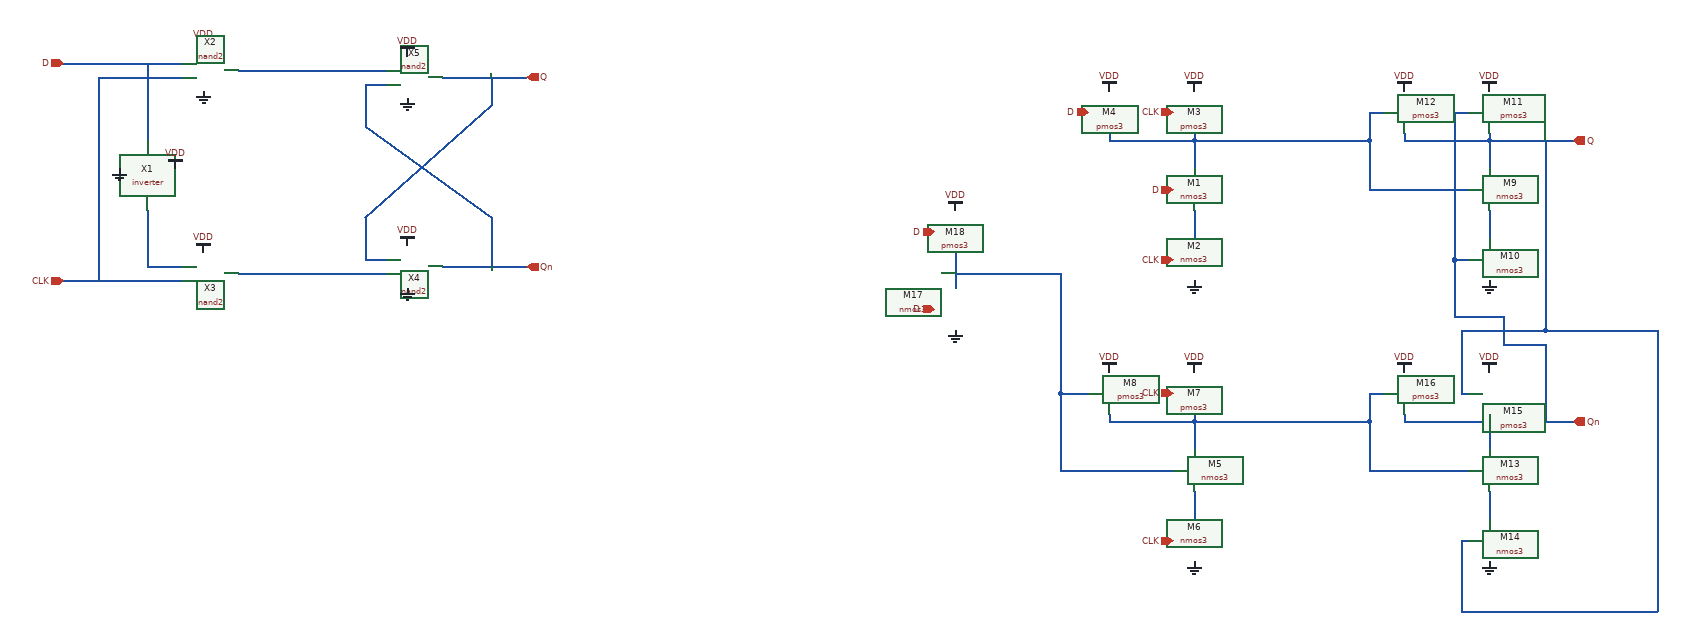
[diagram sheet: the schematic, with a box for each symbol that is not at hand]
v {xschem version=2.9.9 file_version=1.2 }
G {}
K {}
V {}
S {}
E {}
N 240 -670 410 -670 { lab=CLK}
N 240 -980 410 -980 { lab=D}
N 780 -960 900 -960 { lab=Q}
N 780 -690 900 -690 { lab=Qn}
N 490 -970 700 -970 { lab=#net1}
N 490 -680 700 -680 { lab=#net2}
N 670 -700 700 -700 { lab=Q}
N 670 -760 670 -700 { lab=Q}
N 670 -760 850 -920 { lab=Q}
N 850 -960 850 -920 { lab=Q}
N 670 -950 700 -950 { lab=Qn}
N 670 -950 670 -890 { lab=Qn}
N 670 -890 850 -760 { lab=Qn}
N 850 -760 850 -690 { lab=Qn}
N 290 -960 410 -960 { lab=CLK}
N 290 -960 290 -670 { lab=CLK}
N 360 -980 360 -870 { lab=D}
N 360 -770 360 -690 { lab=#net3}
N 360 -690 410 -690 { lab=#net3}
N 1730 -880 1730 -870 { lab=#net4}
N 1730 -870 1850 -870 { lab=#net4}
N 1850 -880 1850 -870 { lab=#net4}
N 1850 -870 1850 -830 { lab=#net4}
N 1850 -770 1850 -730 { lab=#net5}
N 1730 -480 1730 -470 { lab=#net6}
N 1730 -470 1850 -470 { lab=#net6}
N 1850 -480 1850 -470 { lab=#net6}
N 1850 -470 1850 -430 { lab=#net6}
N 1850 -370 1850 -330 { lab=#net7}
N 2150 -880 2150 -870 { lab=Q}
N 2150 -870 2270 -870 { lab=Q}
N 2270 -880 2270 -870 { lab=Q}
N 2270 -870 2270 -830 { lab=Q}
N 2270 -770 2270 -730 { lab=#net8}
N 2150 -480 2150 -470 { lab=#net9}
N 2150 -470 2270 -470 { lab=#net9}
N 2270 -480 2270 -470 { lab=#net9}
N 2270 -470 2270 -430 { lab=#net9}
N 2270 -370 2270 -330 { lab=#net10}
N 1510 -710 1510 -700 { lab=#net11}
N 1510 -700 1510 -660 { lab=#net11}
N 1510 -680 1660 -680 { lab=#net11}
N 1660 -680 1660 -510 { lab=#net11}
N 1660 -510 1700 -510 { lab=#net11}
N 1660 -510 1660 -400 { lab=#net11}
N 1660 -400 1820 -400 { lab=#net11}
N 2270 -870 2390 -870 { lab=Q}
N 2270 -470 2390 -470 { lab=Qn}
N 1850 -870 2100 -870 {}
N 2100 -910 2100 -870 {}
N 2100 -910 2120 -910 {}
N 2100 -870 2100 -800 {}
N 2100 -800 2240 -800 {}
N 1850 -470 2100 -470 {}
N 2100 -510 2100 -470 {}
N 2100 -510 2120 -510 {}
N 2100 -470 2100 -400 {}
N 2100 -400 2240 -400 {}
N 2350 -870 2350 -600 {}
N 2230 -600 2350 -600 {}
N 2230 -600 2230 -510 {}
N 2230 -510 2240 -510 {}
N 2350 -600 2510 -600 {}
N 2510 -600 2510 -200 {}
N 2230 -200 2510 -200 {}
N 2230 -300 2230 -200 {}
N 2230 -300 2240 -300 {}
N 2350 -580 2350 -470 {}
N 2290 -580 2350 -580 {}
N 2290 -620 2290 -580 {}
N 2220 -620 2290 -620 {}
N 2220 -700 2220 -620 {}
N 2220 -700 2240 -700 {}
N 2220 -910 2220 -700 {}
N 2220 -910 2240 -910 {}
C {devices/ipin.sym} 240 -980 0 0 {name=p3 lab=D}
C {devices/iopin.sym} 240 -670 2 0 {name=p7 lab=CLK}
C {devices/opin.sym} 900 -690 0 0 {name=p6 lab=Qn}
C {devices/opin.sym} 900 -960 0 0 {name=p8 lab=Q}
C {madvlsi/vdd.sym} 440 -1000 0 0 {name=l3 lab=VDD}
C {madvlsi/vdd.sym} 440 -710 0 0 {name=l4 lab=VDD}
C {madvlsi/gnd.sym} 440 -940 0 0 {name=l5 lab=GND}
C {madvlsi/gnd.sym} 440 -650 0 0 {name=l6 lab=GND}
C {/home/madvlsi/Documents/MADVLSI-Final_Project/schematic/nand2.sym} 370 -970 0 0 {name=X2}
C {/home/madvlsi/Documents/MADVLSI-Final_Project/schematic/nand2.sym} 370 -680 0 0 {name=X3}
C {/home/madvlsi/Documents/MADVLSI-Final_Project/schematic/nand2.sym} 660 -690 0 0 {name=X4}
C {/home/madvlsi/Documents/MADVLSI-Final_Project/schematic/nand2.sym} 660 -960 0 0 {name=X5}
C {madvlsi/vdd.sym} 730 -990 0 0 {name=l7 lab=VDD}
C {madvlsi/gnd.sym} 730 -930 0 0 {name=l8 lab=GND}
C {madvlsi/vdd.sym} 730 -720 0 0 {name=l9 lab=VDD}
C {madvlsi/gnd.sym} 730 -660 0 0 {name=l10 lab=GND}
C {/home/madvlsi/Documents/MADVLSI-Final_Project/schematic/inverter.sym} 360 -830 1 0 {name=X1 Wp=1 Lp=0.15 WW=1 LL=0.15}
C {madvlsi/vdd.sym} 400 -830 1 0 {name=l1 lab=VDD}
C {madvlsi/gnd.sym} 320 -830 1 0 {name=l2 lab=GND}
C {madvlsi/nmos3.sym} 1850 -800 0 0 {name=M1
L=0.15
W=1
body=GND
nf=1
mult=1
ad="'int((nf+1)/2) * W/nf * 0.29'" 
pd="'2*int((nf+1)/2) * (W/nf + 0.29)'"
as="'int((nf+2)/2) * W/nf * 0.29'" 
ps="'2*int((nf+2)/2) * (W/nf + 0.29)'"
nrd="'0.29 / W'" nrs="'0.29 / W'"
sa=0 sb=0 sd=0
model=nfet_01v8
spiceprefix=X
}
C {madvlsi/nmos3.sym} 1850 -700 0 0 {name=M2
L=0.15
W=1
body=GND
nf=1
mult=1
ad="'int((nf+1)/2) * W/nf * 0.29'" 
pd="'2*int((nf+1)/2) * (W/nf + 0.29)'"
as="'int((nf+2)/2) * W/nf * 0.29'" 
ps="'2*int((nf+2)/2) * (W/nf + 0.29)'"
nrd="'0.29 / W'" nrs="'0.29 / W'"
sa=0 sb=0 sd=0
model=nfet_01v8
spiceprefix=X
}
C {madvlsi/pmos3.sym} 1850 -910 0 0 {name=M3
L=0.15
W=1
body=VDD
nf=1
mult=1
ad="'int((nf+1)/2) * W/nf * 0.29'" 
pd="'2*int((nf+1)/2) * (W/nf + 0.29)'"
as="'int((nf+2)/2) * W/nf * 0.29'" 
ps="'2*int((nf+2)/2) * (W/nf + 0.29)'"
nrd="'0.29 / W'" nrs="'0.29 / W'"
sa=0 sb=0 sd=0
model=pfet_01v8
spiceprefix=X
}
C {madvlsi/pmos3.sym} 1730 -910 0 0 {name=M4
L=0.15
W=1
body=VDD
nf=1
mult=1
ad="'int((nf+1)/2) * W/nf * 0.29'" 
pd="'2*int((nf+1)/2) * (W/nf + 0.29)'"
as="'int((nf+2)/2) * W/nf * 0.29'" 
ps="'2*int((nf+2)/2) * (W/nf + 0.29)'"
nrd="'0.29 / W'" nrs="'0.29 / W'"
sa=0 sb=0 sd=0
model=pfet_01v8
spiceprefix=X
}
C {madvlsi/vdd.sym} 1730 -940 0 0 {name=l11 lab=VDD}
C {madvlsi/vdd.sym} 1850 -940 0 0 {name=l12 lab=VDD}
C {madvlsi/gnd.sym} 1850 -670 0 0 {name=l13 lab=GND}
C {madvlsi/nmos3.sym} 1850 -400 0 0 {name=M5
L=0.15
W=1
body=GND
nf=1
mult=1
ad="'int((nf+1)/2) * W/nf * 0.29'" 
pd="'2*int((nf+1)/2) * (W/nf + 0.29)'"
as="'int((nf+2)/2) * W/nf * 0.29'" 
ps="'2*int((nf+2)/2) * (W/nf + 0.29)'"
nrd="'0.29 / W'" nrs="'0.29 / W'"
sa=0 sb=0 sd=0
model=nfet_01v8
spiceprefix=X
}
C {madvlsi/nmos3.sym} 1850 -300 0 0 {name=M6
L=0.15
W=1
body=GND
nf=1
mult=1
ad="'int((nf+1)/2) * W/nf * 0.29'" 
pd="'2*int((nf+1)/2) * (W/nf + 0.29)'"
as="'int((nf+2)/2) * W/nf * 0.29'" 
ps="'2*int((nf+2)/2) * (W/nf + 0.29)'"
nrd="'0.29 / W'" nrs="'0.29 / W'"
sa=0 sb=0 sd=0
model=nfet_01v8
spiceprefix=X
}
C {madvlsi/pmos3.sym} 1850 -510 0 0 {name=M7
L=0.15
W=1
body=VDD
nf=1
mult=1
ad="'int((nf+1)/2) * W/nf * 0.29'" 
pd="'2*int((nf+1)/2) * (W/nf + 0.29)'"
as="'int((nf+2)/2) * W/nf * 0.29'" 
ps="'2*int((nf+2)/2) * (W/nf + 0.29)'"
nrd="'0.29 / W'" nrs="'0.29 / W'"
sa=0 sb=0 sd=0
model=pfet_01v8
spiceprefix=X
}
C {madvlsi/pmos3.sym} 1730 -510 0 0 {name=M8
L=0.15
W=1
body=VDD
nf=1
mult=1
ad="'int((nf+1)/2) * W/nf * 0.29'" 
pd="'2*int((nf+1)/2) * (W/nf + 0.29)'"
as="'int((nf+2)/2) * W/nf * 0.29'" 
ps="'2*int((nf+2)/2) * (W/nf + 0.29)'"
nrd="'0.29 / W'" nrs="'0.29 / W'"
sa=0 sb=0 sd=0
model=pfet_01v8
spiceprefix=X
}
C {madvlsi/vdd.sym} 1730 -540 0 0 {name=l14 lab=VDD}
C {madvlsi/vdd.sym} 1850 -540 0 0 {name=l15 lab=VDD}
C {madvlsi/gnd.sym} 1850 -270 0 0 {name=l16 lab=GND}
C {madvlsi/nmos3.sym} 2270 -800 0 0 {name=M9
L=0.15
W=1
body=GND
nf=1
mult=1
ad="'int((nf+1)/2) * W/nf * 0.29'" 
pd="'2*int((nf+1)/2) * (W/nf + 0.29)'"
as="'int((nf+2)/2) * W/nf * 0.29'" 
ps="'2*int((nf+2)/2) * (W/nf + 0.29)'"
nrd="'0.29 / W'" nrs="'0.29 / W'"
sa=0 sb=0 sd=0
model=nfet_01v8
spiceprefix=X
}
C {madvlsi/nmos3.sym} 2270 -700 0 0 {name=M10
L=0.15
W=1
body=GND
nf=1
mult=1
ad="'int((nf+1)/2) * W/nf * 0.29'" 
pd="'2*int((nf+1)/2) * (W/nf + 0.29)'"
as="'int((nf+2)/2) * W/nf * 0.29'" 
ps="'2*int((nf+2)/2) * (W/nf + 0.29)'"
nrd="'0.29 / W'" nrs="'0.29 / W'"
sa=0 sb=0 sd=0
model=nfet_01v8
spiceprefix=X
}
C {madvlsi/pmos3.sym} 2270 -910 0 0 {name=M11
L=0.15
W=1
body=VDD
nf=1
mult=1
ad="'int((nf+1)/2) * W/nf * 0.29'" 
pd="'2*int((nf+1)/2) * (W/nf + 0.29)'"
as="'int((nf+2)/2) * W/nf * 0.29'" 
ps="'2*int((nf+2)/2) * (W/nf + 0.29)'"
nrd="'0.29 / W'" nrs="'0.29 / W'"
sa=0 sb=0 sd=0
model=pfet_01v8
spiceprefix=X
}
C {madvlsi/pmos3.sym} 2150 -910 0 0 {name=M12
L=0.15
W=1
body=VDD
nf=1
mult=1
ad="'int((nf+1)/2) * W/nf * 0.29'" 
pd="'2*int((nf+1)/2) * (W/nf + 0.29)'"
as="'int((nf+2)/2) * W/nf * 0.29'" 
ps="'2*int((nf+2)/2) * (W/nf + 0.29)'"
nrd="'0.29 / W'" nrs="'0.29 / W'"
sa=0 sb=0 sd=0
model=pfet_01v8
spiceprefix=X
}
C {madvlsi/vdd.sym} 2150 -940 0 0 {name=l17 lab=VDD}
C {madvlsi/vdd.sym} 2270 -940 0 0 {name=l18 lab=VDD}
C {madvlsi/gnd.sym} 2270 -670 0 0 {name=l19 lab=GND}
C {madvlsi/nmos3.sym} 2270 -400 0 0 {name=M13
L=0.15
W=1
body=GND
nf=1
mult=1
ad="'int((nf+1)/2) * W/nf * 0.29'" 
pd="'2*int((nf+1)/2) * (W/nf + 0.29)'"
as="'int((nf+2)/2) * W/nf * 0.29'" 
ps="'2*int((nf+2)/2) * (W/nf + 0.29)'"
nrd="'0.29 / W'" nrs="'0.29 / W'"
sa=0 sb=0 sd=0
model=nfet_01v8
spiceprefix=X
}
C {madvlsi/nmos3.sym} 2270 -300 0 0 {name=M14
L=0.15
W=1
body=GND
nf=1
mult=1
ad="'int((nf+1)/2) * W/nf * 0.29'" 
pd="'2*int((nf+1)/2) * (W/nf + 0.29)'"
as="'int((nf+2)/2) * W/nf * 0.29'" 
ps="'2*int((nf+2)/2) * (W/nf + 0.29)'"
nrd="'0.29 / W'" nrs="'0.29 / W'"
sa=0 sb=0 sd=0
model=nfet_01v8
spiceprefix=X
}
C {madvlsi/pmos3.sym} 2270 -510 0 0 {name=M15
L=0.15
W=1
body=VDD
nf=1
mult=1
ad="'int((nf+1)/2) * W/nf * 0.29'" 
pd="'2*int((nf+1)/2) * (W/nf + 0.29)'"
as="'int((nf+2)/2) * W/nf * 0.29'" 
ps="'2*int((nf+2)/2) * (W/nf + 0.29)'"
nrd="'0.29 / W'" nrs="'0.29 / W'"
sa=0 sb=0 sd=0
model=pfet_01v8
spiceprefix=X
}
C {madvlsi/pmos3.sym} 2150 -510 0 0 {name=M16
L=0.15
W=1
body=VDD
nf=1
mult=1
ad="'int((nf+1)/2) * W/nf * 0.29'" 
pd="'2*int((nf+1)/2) * (W/nf + 0.29)'"
as="'int((nf+2)/2) * W/nf * 0.29'" 
ps="'2*int((nf+2)/2) * (W/nf + 0.29)'"
nrd="'0.29 / W'" nrs="'0.29 / W'"
sa=0 sb=0 sd=0
model=pfet_01v8
spiceprefix=X
}
C {madvlsi/vdd.sym} 2150 -540 0 0 {name=l20 lab=VDD}
C {madvlsi/vdd.sym} 2270 -540 0 0 {name=l21 lab=VDD}
C {madvlsi/gnd.sym} 2270 -270 0 0 {name=l22 lab=GND}
C {madvlsi/nmos3.sym} 1510 -630 0 0 {name=M17
L=0.15
W=1
body=GND
nf=1
mult=1
ad="'int((nf+1)/2) * W/nf * 0.29'" 
pd="'2*int((nf+1)/2) * (W/nf + 0.29)'"
as="'int((nf+2)/2) * W/nf * 0.29'" 
ps="'2*int((nf+2)/2) * (W/nf + 0.29)'"
nrd="'0.29 / W'" nrs="'0.29 / W'"
sa=0 sb=0 sd=0
model=nfet_01v8
spiceprefix=X
}
C {madvlsi/pmos3.sym} 1510 -740 0 0 {name=M18
L=0.15
W=1
body=VDD
nf=1
mult=1
ad="'int((nf+1)/2) * W/nf * 0.29'" 
pd="'2*int((nf+1)/2) * (W/nf + 0.29)'"
as="'int((nf+2)/2) * W/nf * 0.29'" 
ps="'2*int((nf+2)/2) * (W/nf + 0.29)'"
nrd="'0.29 / W'" nrs="'0.29 / W'"
sa=0 sb=0 sd=0
model=pfet_01v8
spiceprefix=X
}
C {madvlsi/vdd.sym} 1510 -770 0 0 {name=l23 lab=VDD}
C {madvlsi/gnd.sym} 1510 -600 0 0 {name=l24 lab=GND}
C {devices/ipin.sym} 1700 -910 0 0 {name=p1 lab=D}
C {devices/ipin.sym} 1820 -800 0 0 {name=p2 lab=D}
C {devices/ipin.sym} 1480 -740 0 0 {name=p4 lab=D}
C {devices/ipin.sym} 1480 -630 0 0 {name=p5 lab=D}
C {devices/iopin.sym} 1820 -910 2 0 {name=p9 lab=CLK}
C {devices/iopin.sym} 1820 -700 2 0 {name=p10 lab=CLK}
C {devices/iopin.sym} 1820 -510 2 0 {name=p11 lab=CLK}
C {devices/iopin.sym} 1820 -300 2 0 {name=p12 lab=CLK}
C {devices/opin.sym} 2390 -870 0 0 {name=p13 lab=Q}
C {devices/opin.sym} 2390 -470 0 0 {name=p14 lab=Qn}
